VERSION 5.7 ;
  NOWIREEXTENSIONATPIN ON ;
  DIVIDERCHAR "/" ;
  BUSBITCHARS "[]" ;
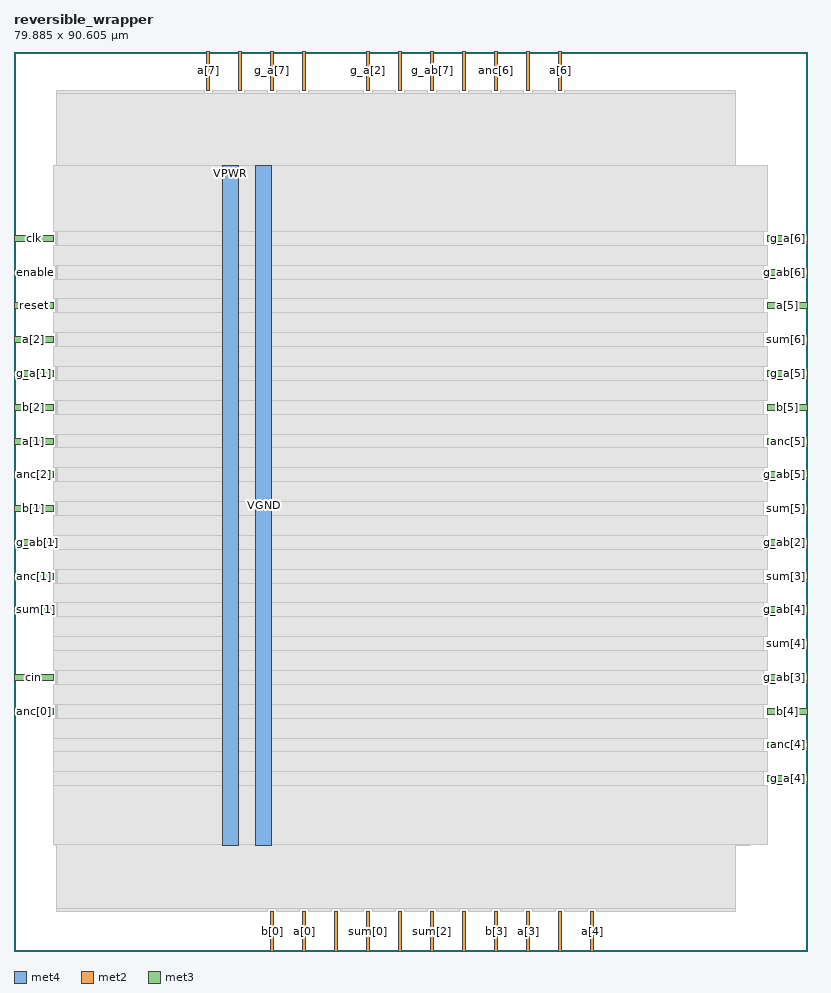
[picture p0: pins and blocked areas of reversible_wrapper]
MACRO reversible_wrapper
  CLASS BLOCK ;
  FOREIGN reversible_wrapper ;
  ORIGIN 0.000 0.000 ;
  SIZE 79.885 BY 90.605 ;
  PIN VGND
    DIRECTION INOUT ;
    USE GROUND ;
    PORT
      LAYER met4 ;
        RECT 24.340 10.640 25.940 79.120 ;
    END
  END VGND
  PIN VPWR
    DIRECTION INOUT ;
    USE POWER ;
    PORT
      LAYER met4 ;
        RECT 21.040 10.640 22.640 79.120 ;
    END
  END VPWR
  PIN a[0]
    DIRECTION INPUT ;
    USE SIGNAL ;
    ANTENNAGATEAREA 0.196500 ;
    PORT
      LAYER met2 ;
        RECT 29.070 0.000 29.350 4.000 ;
    END
  END a[0]
  PIN a[1]
    DIRECTION INPUT ;
    USE SIGNAL ;
    ANTENNAGATEAREA 0.196500 ;
    PORT
      LAYER met3 ;
        RECT 0.000 51.040 4.000 51.640 ;
    END
  END a[1]
  PIN a[2]
    DIRECTION INPUT ;
    USE SIGNAL ;
    ANTENNAGATEAREA 0.196500 ;
    PORT
      LAYER met3 ;
        RECT 0.000 61.240 4.000 61.840 ;
    END
  END a[2]
  PIN a[3]
    DIRECTION INPUT ;
    USE SIGNAL ;
    ANTENNAGATEAREA 0.196500 ;
    PORT
      LAYER met2 ;
        RECT 51.610 0.000 51.890 4.000 ;
    END
  END a[3]
  PIN a[4]
    DIRECTION INPUT ;
    USE SIGNAL ;
    ANTENNAGATEAREA 0.196500 ;
    PORT
      LAYER met2 ;
        RECT 58.050 0.000 58.330 4.000 ;
    END
  END a[4]
  PIN a[5]
    DIRECTION INPUT ;
    USE SIGNAL ;
    ANTENNAGATEAREA 0.196500 ;
    PORT
      LAYER met3 ;
        RECT 75.885 64.640 79.885 65.240 ;
    END
  END a[5]
  PIN a[6]
    DIRECTION INPUT ;
    USE SIGNAL ;
    ANTENNAGATEAREA 0.196500 ;
    PORT
      LAYER met2 ;
        RECT 54.830 86.605 55.110 90.605 ;
    END
  END a[6]
  PIN a[7]
    DIRECTION INPUT ;
    USE SIGNAL ;
    ANTENNAGATEAREA 0.196500 ;
    PORT
      LAYER met2 ;
        RECT 19.410 86.605 19.690 90.605 ;
    END
  END a[7]
  PIN anc[0]
    DIRECTION INPUT ;
    USE SIGNAL ;
    ANTENNAGATEAREA 0.196500 ;
    PORT
      LAYER met3 ;
        RECT 0.000 23.840 4.000 24.440 ;
    END
  END anc[0]
  PIN anc[1]
    DIRECTION INPUT ;
    USE SIGNAL ;
    ANTENNAGATEAREA 0.196500 ;
    PORT
      LAYER met3 ;
        RECT 0.000 37.440 4.000 38.040 ;
    END
  END anc[1]
  PIN anc[2]
    DIRECTION INPUT ;
    USE SIGNAL ;
    ANTENNAGATEAREA 0.196500 ;
    PORT
      LAYER met3 ;
        RECT 0.000 47.640 4.000 48.240 ;
    END
  END anc[2]
  PIN anc[3]
    DIRECTION INPUT ;
    USE SIGNAL ;
    ANTENNAGATEAREA 0.196500 ;
    PORT
      LAYER met2 ;
        RECT 45.170 0.000 45.450 4.000 ;
    END
  END anc[3]
  PIN anc[4]
    DIRECTION INPUT ;
    USE SIGNAL ;
    ANTENNAGATEAREA 0.196500 ;
    PORT
      LAYER met3 ;
        RECT 75.885 20.440 79.885 21.040 ;
    END
  END anc[4]
  PIN anc[5]
    DIRECTION INPUT ;
    USE SIGNAL ;
    ANTENNAGATEAREA 0.196500 ;
    PORT
      LAYER met3 ;
        RECT 75.885 51.040 79.885 51.640 ;
    END
  END anc[5]
  PIN anc[6]
    DIRECTION INPUT ;
    USE SIGNAL ;
    ANTENNAGATEAREA 0.196500 ;
    PORT
      LAYER met2 ;
        RECT 48.390 86.605 48.670 90.605 ;
    END
  END anc[6]
  PIN anc[7]
    DIRECTION INPUT ;
    USE SIGNAL ;
    ANTENNAGATEAREA 0.196500 ;
    PORT
      LAYER met2 ;
        RECT 29.070 86.605 29.350 90.605 ;
    END
  END anc[7]
  PIN b[0]
    DIRECTION INPUT ;
    USE SIGNAL ;
    ANTENNAGATEAREA 0.196500 ;
    PORT
      LAYER met2 ;
        RECT 25.850 0.000 26.130 4.000 ;
    END
  END b[0]
  PIN b[1]
    DIRECTION INPUT ;
    USE SIGNAL ;
    ANTENNAGATEAREA 0.196500 ;
    PORT
      LAYER met3 ;
        RECT 0.000 44.240 4.000 44.840 ;
    END
  END b[1]
  PIN b[2]
    DIRECTION INPUT ;
    USE SIGNAL ;
    ANTENNAGATEAREA 0.196500 ;
    PORT
      LAYER met3 ;
        RECT 0.000 54.440 4.000 55.040 ;
    END
  END b[2]
  PIN b[3]
    DIRECTION INPUT ;
    USE SIGNAL ;
    ANTENNAGATEAREA 0.196500 ;
    PORT
      LAYER met2 ;
        RECT 48.390 0.000 48.670 4.000 ;
    END
  END b[3]
  PIN b[4]
    DIRECTION INPUT ;
    USE SIGNAL ;
    ANTENNAGATEAREA 0.196500 ;
    PORT
      LAYER met3 ;
        RECT 75.885 23.840 79.885 24.440 ;
    END
  END b[4]
  PIN b[5]
    DIRECTION INPUT ;
    USE SIGNAL ;
    ANTENNAGATEAREA 0.196500 ;
    PORT
      LAYER met3 ;
        RECT 75.885 54.440 79.885 55.040 ;
    END
  END b[5]
  PIN b[6]
    DIRECTION INPUT ;
    USE SIGNAL ;
    ANTENNAGATEAREA 0.196500 ;
    PORT
      LAYER met2 ;
        RECT 51.610 86.605 51.890 90.605 ;
    END
  END b[6]
  PIN b[7]
    DIRECTION INPUT ;
    USE SIGNAL ;
    ANTENNAGATEAREA 0.196500 ;
    PORT
      LAYER met2 ;
        RECT 22.630 86.605 22.910 90.605 ;
    END
  END b[7]
  PIN cin
    DIRECTION INPUT ;
    USE SIGNAL ;
    ANTENNAGATEAREA 0.196500 ;
    PORT
      LAYER met3 ;
        RECT 0.000 27.240 4.000 27.840 ;
    END
  END cin
  PIN clk
    DIRECTION INPUT ;
    USE SIGNAL ;
    ANTENNAGATEAREA 0.852000 ;
    PORT
      LAYER met3 ;
        RECT 0.000 71.440 4.000 72.040 ;
    END
  END clk
  PIN cout
    DIRECTION OUTPUT ;
    USE SIGNAL ;
    ANTENNADIFFAREA 0.445500 ;
    PORT
      LAYER met2 ;
        RECT 38.730 86.605 39.010 90.605 ;
    END
  END cout
  PIN enable
    DIRECTION INPUT ;
    USE SIGNAL ;
    ANTENNAGATEAREA 0.196500 ;
    PORT
      LAYER met3 ;
        RECT 0.000 68.040 4.000 68.640 ;
    END
  END enable
  PIN g_a[0]
    DIRECTION OUTPUT ;
    USE SIGNAL ;
    ANTENNADIFFAREA 0.445500 ;
    PORT
      LAYER met2 ;
        RECT 38.730 0.000 39.010 4.000 ;
    END
  END g_a[0]
  PIN g_a[1]
    DIRECTION OUTPUT ;
    USE SIGNAL ;
    ANTENNADIFFAREA 0.445500 ;
    PORT
      LAYER met3 ;
        RECT 0.000 57.840 4.000 58.440 ;
    END
  END g_a[1]
  PIN g_a[2]
    DIRECTION OUTPUT ;
    USE SIGNAL ;
    ANTENNADIFFAREA 0.445500 ;
    PORT
      LAYER met2 ;
        RECT 35.510 86.605 35.790 90.605 ;
    END
  END g_a[2]
  PIN g_a[3]
    DIRECTION OUTPUT ;
    USE SIGNAL ;
    ANTENNADIFFAREA 0.445500 ;
    PORT
      LAYER met2 ;
        RECT 54.830 0.000 55.110 4.000 ;
    END
  END g_a[3]
  PIN g_a[4]
    DIRECTION OUTPUT ;
    USE SIGNAL ;
    ANTENNADIFFAREA 0.445500 ;
    PORT
      LAYER met3 ;
        RECT 75.885 17.040 79.885 17.640 ;
    END
  END g_a[4]
  PIN g_a[5]
    DIRECTION OUTPUT ;
    USE SIGNAL ;
    ANTENNADIFFAREA 0.445500 ;
    PORT
      LAYER met3 ;
        RECT 75.885 57.840 79.885 58.440 ;
    END
  END g_a[5]
  PIN g_a[6]
    DIRECTION OUTPUT ;
    USE SIGNAL ;
    ANTENNADIFFAREA 0.445500 ;
    PORT
      LAYER met3 ;
        RECT 75.885 71.440 79.885 72.040 ;
    END
  END g_a[6]
  PIN g_a[7]
    DIRECTION OUTPUT ;
    USE SIGNAL ;
    ANTENNADIFFAREA 0.445500 ;
    PORT
      LAYER met2 ;
        RECT 25.850 86.605 26.130 90.605 ;
    END
  END g_a[7]
  PIN g_ab[0]
    DIRECTION OUTPUT ;
    USE SIGNAL ;
    ANTENNADIFFAREA 0.445500 ;
    PORT
      LAYER met2 ;
        RECT 32.290 0.000 32.570 4.000 ;
    END
  END g_ab[0]
  PIN g_ab[1]
    DIRECTION OUTPUT ;
    USE SIGNAL ;
    ANTENNADIFFAREA 0.445500 ;
    PORT
      LAYER met3 ;
        RECT 0.000 40.840 4.000 41.440 ;
    END
  END g_ab[1]
  PIN g_ab[2]
    DIRECTION OUTPUT ;
    USE SIGNAL ;
    ANTENNADIFFAREA 0.445500 ;
    PORT
      LAYER met3 ;
        RECT 75.885 40.840 79.885 41.440 ;
    END
  END g_ab[2]
  PIN g_ab[3]
    DIRECTION OUTPUT ;
    USE SIGNAL ;
    ANTENNADIFFAREA 0.445500 ;
    PORT
      LAYER met3 ;
        RECT 75.885 27.240 79.885 27.840 ;
    END
  END g_ab[3]
  PIN g_ab[4]
    DIRECTION OUTPUT ;
    USE SIGNAL ;
    ANTENNADIFFAREA 0.445500 ;
    PORT
      LAYER met3 ;
        RECT 75.885 34.040 79.885 34.640 ;
    END
  END g_ab[4]
  PIN g_ab[5]
    DIRECTION OUTPUT ;
    USE SIGNAL ;
    ANTENNADIFFAREA 0.445500 ;
    PORT
      LAYER met3 ;
        RECT 75.885 47.640 79.885 48.240 ;
    END
  END g_ab[5]
  PIN g_ab[6]
    DIRECTION OUTPUT ;
    USE SIGNAL ;
    ANTENNADIFFAREA 0.445500 ;
    PORT
      LAYER met3 ;
        RECT 75.885 68.040 79.885 68.640 ;
    END
  END g_ab[6]
  PIN g_ab[7]
    DIRECTION OUTPUT ;
    USE SIGNAL ;
    ANTENNADIFFAREA 0.445500 ;
    PORT
      LAYER met2 ;
        RECT 41.950 86.605 42.230 90.605 ;
    END
  END g_ab[7]
  PIN reset
    DIRECTION INPUT ;
    USE SIGNAL ;
    ANTENNAGATEAREA 0.196500 ;
    PORT
      LAYER met3 ;
        RECT 0.000 64.640 4.000 65.240 ;
    END
  END reset
  PIN sum[0]
    DIRECTION OUTPUT ;
    USE SIGNAL ;
    ANTENNADIFFAREA 0.445500 ;
    PORT
      LAYER met2 ;
        RECT 35.510 0.000 35.790 4.000 ;
    END
  END sum[0]
  PIN sum[1]
    DIRECTION OUTPUT ;
    USE SIGNAL ;
    ANTENNADIFFAREA 0.445500 ;
    PORT
      LAYER met3 ;
        RECT 0.000 34.040 4.000 34.640 ;
    END
  END sum[1]
  PIN sum[2]
    DIRECTION OUTPUT ;
    USE SIGNAL ;
    ANTENNADIFFAREA 0.445500 ;
    PORT
      LAYER met2 ;
        RECT 41.950 0.000 42.230 4.000 ;
    END
  END sum[2]
  PIN sum[3]
    DIRECTION OUTPUT ;
    USE SIGNAL ;
    ANTENNADIFFAREA 0.445500 ;
    PORT
      LAYER met3 ;
        RECT 75.885 37.440 79.885 38.040 ;
    END
  END sum[3]
  PIN sum[4]
    DIRECTION OUTPUT ;
    USE SIGNAL ;
    ANTENNADIFFAREA 0.445500 ;
    PORT
      LAYER met3 ;
        RECT 75.885 30.640 79.885 31.240 ;
    END
  END sum[4]
  PIN sum[5]
    DIRECTION OUTPUT ;
    USE SIGNAL ;
    ANTENNADIFFAREA 0.445500 ;
    PORT
      LAYER met3 ;
        RECT 75.885 44.240 79.885 44.840 ;
    END
  END sum[5]
  PIN sum[6]
    DIRECTION OUTPUT ;
    USE SIGNAL ;
    ANTENNADIFFAREA 0.445500 ;
    PORT
      LAYER met3 ;
        RECT 75.885 61.240 79.885 61.840 ;
    END
  END sum[6]
  PIN sum[7]
    DIRECTION OUTPUT ;
    USE SIGNAL ;
    ANTENNADIFFAREA 0.445500 ;
    PORT
      LAYER met2 ;
        RECT 45.170 86.605 45.450 90.605 ;
    END
  END sum[7]
  OBS
      LAYER nwell ;
        RECT 5.330 10.795 74.250 79.070 ;
      LAYER li1 ;
        RECT 5.520 10.795 74.060 78.965 ;
      LAYER met1 ;
        RECT 4.210 10.640 74.060 79.120 ;
      LAYER met2 ;
        RECT 4.230 86.325 19.130 86.605 ;
        RECT 19.970 86.325 22.350 86.605 ;
        RECT 23.190 86.325 25.570 86.605 ;
        RECT 26.410 86.325 28.790 86.605 ;
        RECT 29.630 86.325 35.230 86.605 ;
        RECT 36.070 86.325 38.450 86.605 ;
        RECT 39.290 86.325 41.670 86.605 ;
        RECT 42.510 86.325 44.890 86.605 ;
        RECT 45.730 86.325 48.110 86.605 ;
        RECT 48.950 86.325 51.330 86.605 ;
        RECT 52.170 86.325 54.550 86.605 ;
        RECT 55.390 86.325 72.590 86.605 ;
        RECT 4.230 4.280 72.590 86.325 ;
        RECT 4.230 4.000 25.570 4.280 ;
        RECT 26.410 4.000 28.790 4.280 ;
        RECT 29.630 4.000 32.010 4.280 ;
        RECT 32.850 4.000 35.230 4.280 ;
        RECT 36.070 4.000 38.450 4.280 ;
        RECT 39.290 4.000 41.670 4.280 ;
        RECT 42.510 4.000 44.890 4.280 ;
        RECT 45.730 4.000 48.110 4.280 ;
        RECT 48.950 4.000 51.330 4.280 ;
        RECT 52.170 4.000 54.550 4.280 ;
        RECT 55.390 4.000 57.770 4.280 ;
        RECT 58.610 4.000 72.590 4.280 ;
      LAYER met3 ;
        RECT 3.990 72.440 75.885 79.045 ;
        RECT 4.400 71.040 75.485 72.440 ;
        RECT 3.990 69.040 75.885 71.040 ;
        RECT 4.400 67.640 75.485 69.040 ;
        RECT 3.990 65.640 75.885 67.640 ;
        RECT 4.400 64.240 75.485 65.640 ;
        RECT 3.990 62.240 75.885 64.240 ;
        RECT 4.400 60.840 75.485 62.240 ;
        RECT 3.990 58.840 75.885 60.840 ;
        RECT 4.400 57.440 75.485 58.840 ;
        RECT 3.990 55.440 75.885 57.440 ;
        RECT 4.400 54.040 75.485 55.440 ;
        RECT 3.990 52.040 75.885 54.040 ;
        RECT 4.400 50.640 75.485 52.040 ;
        RECT 3.990 48.640 75.885 50.640 ;
        RECT 4.400 47.240 75.485 48.640 ;
        RECT 3.990 45.240 75.885 47.240 ;
        RECT 4.400 43.840 75.485 45.240 ;
        RECT 3.990 41.840 75.885 43.840 ;
        RECT 4.400 40.440 75.485 41.840 ;
        RECT 3.990 38.440 75.885 40.440 ;
        RECT 4.400 37.040 75.485 38.440 ;
        RECT 3.990 35.040 75.885 37.040 ;
        RECT 4.400 33.640 75.485 35.040 ;
        RECT 3.990 31.640 75.885 33.640 ;
        RECT 3.990 30.240 75.485 31.640 ;
        RECT 3.990 28.240 75.885 30.240 ;
        RECT 4.400 26.840 75.485 28.240 ;
        RECT 3.990 24.840 75.885 26.840 ;
        RECT 4.400 23.440 75.485 24.840 ;
        RECT 3.990 21.440 75.885 23.440 ;
        RECT 3.990 20.040 75.485 21.440 ;
        RECT 3.990 18.040 75.885 20.040 ;
        RECT 3.990 16.640 75.485 18.040 ;
        RECT 3.990 10.715 75.885 16.640 ;
  END
END reversible_wrapper
END LIBRARY

